VERSION 5.8 ;
BUSBITCHARS "[]" ;
DIVIDERCHAR "/" ;
UNITS
    DATABASE MICRONS 1000 ;
END UNITS

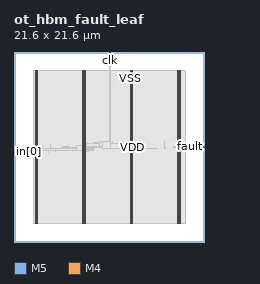
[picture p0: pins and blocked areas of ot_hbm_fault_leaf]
MACRO ot_hbm_fault_leaf
  FOREIGN ot_hbm_fault_leaf 0 0 ;
  CLASS BLOCK ;
  SIZE 21.6 BY 21.6 ;
  PIN clk
    DIRECTION INPUT ;
    USE SIGNAL ;
    PORT
      LAYER M5 ;
        RECT  10.896 21.516 10.92 21.6 ;
    END
  END clk
  PIN fault
    DIRECTION OUTPUT ;
    USE SIGNAL ;
    PORT
      LAYER M4 ;
        RECT  21.516 10.8 21.6 10.824 ;
    END
    PORT
      LAYER M4 ;
        RECT  20.473 10.8 21.564 10.824 ;
    END
  END fault
  PIN in[0]
    DIRECTION INPUT ;
    USE SIGNAL ;
    PORT
      LAYER M4 ;
        RECT  0 10.32 0.084 10.344 ;
    END
  END in[0]
  PIN in[1]
    DIRECTION INPUT ;
    USE SIGNAL ;
    PORT
      LAYER M4 ;
        RECT  0 10.416 0.084 10.44 ;
    END
  END in[1]
  PIN in[2]
    DIRECTION INPUT ;
    USE SIGNAL ;
    PORT
      LAYER M4 ;
        RECT  0 10.512 0.084 10.536 ;
    END
  END in[2]
  PIN in[3]
    DIRECTION INPUT ;
    USE SIGNAL ;
    PORT
      LAYER M4 ;
        RECT  0 10.608 0.084 10.632 ;
    END
  END in[3]
  PIN in[4]
    DIRECTION INPUT ;
    USE SIGNAL ;
    PORT
      LAYER M4 ;
        RECT  0 10.704 0.084 10.728 ;
    END
  END in[4]
  PIN rst_n
    DIRECTION INPUT ;
    USE SIGNAL ;
    PORT
      LAYER M5 ;
        RECT  10.992 21.516 11.016 21.6 ;
    END
  END rst_n
  PIN VDD
    DIRECTION INOUT ;
    USE POWER ;
    PORT
      LAYER M5 ;
        RECT  18.792 2.151 18.912 19.449 ;
        RECT  13.392 2.151 13.512 19.449 ;
        RECT  7.992 2.151 8.112 19.449 ;
        RECT  2.592 2.151 2.712 19.449 ;
    END
  END VDD
  PIN VSS
    DIRECTION INOUT ;
    USE GROUND ;
    PORT
      LAYER M5 ;
        RECT  18.6 2.137 18.72 19.463 ;
        RECT  13.2 2.137 13.32 19.463 ;
        RECT  7.8 2.137 7.92 19.463 ;
        RECT  2.4 2.137 2.52 19.463 ;
    END
  END VSS
  # OT_OBS_CLOSED layer=M5 d_um=1.536 added=0
  OBS
    LAYER RVTN ;
     RECT  2.16 2.16 19.44 2.295 ;
     RECT  2.16 2.565 19.44 2.835 ;
     RECT  2.16 3.105 19.44 3.375 ;
     RECT  2.16 3.645 19.44 3.915 ;
     RECT  2.16 4.185 19.44 4.455 ;
     RECT  2.16 4.725 19.44 4.995 ;
     RECT  2.16 5.265 19.44 5.535 ;
     RECT  2.16 5.805 19.44 6.075 ;
     RECT  2.16 6.345 19.44 6.615 ;
     RECT  2.16 6.885 19.44 7.155 ;
     RECT  2.16 7.425 19.44 7.695 ;
     RECT  2.16 7.965 19.44 8.235 ;
     RECT  2.16 8.505 19.44 8.775 ;
     RECT  2.16 9.045 19.44 9.315 ;
     RECT  2.16 9.585 19.44 9.855 ;
     RECT  2.16 10.125 19.44 10.395 ;
     RECT  2.16 10.665 19.44 10.935 ;
     RECT  2.16 11.205 19.44 11.475 ;
     RECT  2.16 11.745 19.44 12.015 ;
     RECT  2.16 12.285 19.44 12.555 ;
     RECT  2.16 12.825 19.44 13.095 ;
     RECT  2.16 13.365 19.44 13.635 ;
     RECT  2.16 13.905 19.44 14.175 ;
     RECT  2.16 14.445 19.44 14.715 ;
     RECT  2.16 14.985 19.44 15.255 ;
     RECT  2.16 15.525 19.44 15.795 ;
     RECT  2.16 16.065 19.44 16.335 ;
     RECT  2.16 16.605 19.44 16.875 ;
     RECT  2.16 17.145 19.44 17.415 ;
     RECT  2.16 17.685 19.44 17.955 ;
     RECT  2.16 18.225 19.44 18.495 ;
     RECT  2.16 18.765 19.44 19.035 ;
     RECT  2.16 19.305 19.44 19.44 ;
    LAYER RVTP ;
     RECT  2.16 2.295 19.44 2.565 ;
     RECT  2.16 2.835 19.44 3.105 ;
     RECT  2.16 3.375 19.44 3.645 ;
     RECT  2.16 3.915 19.44 4.185 ;
     RECT  2.16 4.455 19.44 4.725 ;
     RECT  2.16 4.995 19.44 5.265 ;
     RECT  2.16 5.535 19.44 5.805 ;
     RECT  2.16 6.075 19.44 6.345 ;
     RECT  2.16 6.615 19.44 6.885 ;
     RECT  2.16 7.155 19.44 7.425 ;
     RECT  2.16 7.695 19.44 7.965 ;
     RECT  2.16 8.235 19.44 8.505 ;
     RECT  2.16 8.775 19.44 9.045 ;
     RECT  2.16 9.315 19.44 9.585 ;
     RECT  2.16 9.855 19.44 10.125 ;
     RECT  2.16 10.395 19.44 10.665 ;
     RECT  2.16 10.935 19.44 11.205 ;
     RECT  2.16 11.475 19.44 11.745 ;
     RECT  2.16 12.015 19.44 12.285 ;
     RECT  2.16 12.555 19.44 12.825 ;
     RECT  2.16 13.095 19.44 13.365 ;
     RECT  2.16 13.635 19.44 13.905 ;
     RECT  2.16 14.175 19.44 14.445 ;
     RECT  2.16 14.715 19.44 14.985 ;
     RECT  2.16 15.255 19.44 15.525 ;
     RECT  2.16 15.795 19.44 16.065 ;
     RECT  2.16 16.335 19.44 16.605 ;
     RECT  2.16 16.875 19.44 17.145 ;
     RECT  2.16 17.415 19.44 17.685 ;
     RECT  2.16 17.955 19.44 18.225 ;
     RECT  2.16 18.495 19.44 18.765 ;
     RECT  2.16 19.035 19.44 19.305 ;
    LAYER M1 ;
     RECT  2.16 2.151 19.44 19.449 ;
    LAYER M2 ;
     RECT  2.16 2.151 19.44 19.449 ;
     RECT  19.44 10.836 20.507 10.854 ;
    LAYER M3 ;
     RECT  2.415 2.143 2.505 2.413 ;
     RECT  7.815 2.143 7.905 2.413 ;
     RECT  13.215 2.143 13.305 2.413 ;
     RECT  18.615 2.143 18.705 2.413 ;
     RECT  7.815 2.413 8.097 10.291 ;
     RECT  2.415 2.413 2.697 10.315 ;
     RECT  2.304 10.315 2.697 10.357 ;
     RECT  4.716 10.291 4.734 10.363 ;
     RECT  7.815 10.291 8.442 10.363 ;
     RECT  3.96 10.165 3.978 10.399 ;
     RECT  4.716 10.363 4.878 10.399 ;
     RECT  5.832 10.363 5.85 10.399 ;
     RECT  7.272 10.363 8.442 10.399 ;
     RECT  3.96 10.399 6.426 10.435 ;
     RECT  7.272 10.399 9.09 10.435 ;
     RECT  3.96 10.435 9.09 10.463 ;
     RECT  4.104 10.463 9.09 10.471 ;
     RECT  4.104 10.471 9.126 10.589 ;
     RECT  12.384 10.597 12.402 10.603 ;
     RECT  13.215 2.413 13.497 10.603 ;
     RECT  4.104 10.589 4.518 10.625 ;
     RECT  17.244 10.597 17.262 10.633 ;
     RECT  16.272 10.597 16.29 10.637 ;
     RECT  5.4 10.589 9.126 10.697 ;
     RECT  7.092 10.697 9.126 10.705 ;
     RECT  10.044 10.603 10.062 10.705 ;
     RECT  17.1 10.633 17.262 10.733 ;
     RECT  18.615 2.413 18.897 10.741 ;
     RECT  5.4 10.697 6.174 10.769 ;
     RECT  14.832 10.669 14.85 10.769 ;
     RECT  2.304 10.357 3.222 10.781 ;
     RECT  7.092 10.705 10.062 10.859 ;
     RECT  12.384 10.603 13.497 10.859 ;
     RECT  18.18 10.741 18.897 10.859 ;
     RECT  20.484 10.795 20.502 10.859 ;
     RECT  5.652 10.769 6.174 10.895 ;
     RECT  9 10.859 10.062 10.925 ;
     RECT  2.415 10.781 3.222 10.931 ;
     RECT  7.092 10.859 8.19 10.931 ;
     RECT  4.104 10.625 4.194 10.967 ;
     RECT  6.156 10.895 6.174 10.967 ;
     RECT  4.104 10.967 4.122 11.129 ;
     RECT  7.815 10.931 8.19 11.129 ;
     RECT  12.384 10.859 12.402 11.165 ;
     RECT  9 10.925 9.774 11.174 ;
     RECT  9.036 11.174 9.774 11.309 ;
     RECT  11.196 11.281 11.214 11.399 ;
     RECT  17.1 10.733 17.118 11.399 ;
     RECT  9.756 11.309 9.774 11.405 ;
     RECT  10.98 11.509 10.998 11.549 ;
     RECT  2.415 10.931 2.697 19.187 ;
     RECT  7.815 11.129 8.097 19.187 ;
     RECT  13.215 10.859 13.497 19.187 ;
     RECT  18.615 10.859 18.897 19.187 ;
     RECT  2.415 19.187 2.505 19.457 ;
     RECT  7.815 19.187 7.905 19.457 ;
     RECT  13.215 19.187 13.305 19.457 ;
     RECT  18.615 19.187 18.705 19.457 ;
    LAYER M4 ;
     RECT  0.084 10.32 2.252 10.344 ;
     RECT  0.06 10.344 2.252 10.416 ;
     RECT  0.084 10.416 2.252 10.44 ;
     RECT  0.06 10.44 2.252 10.512 ;
     RECT  0.084 10.512 2.252 10.536 ;
     RECT  0.06 10.536 2.252 10.608 ;
     RECT  0.084 10.608 2.252 10.632 ;
     RECT  0.06 10.632 2.252 10.704 ;
     RECT  0.084 10.704 2.252 10.728 ;
     RECT  2.252 10.32 2.408 10.776 ;
     RECT  2.408 2.148 2.512 19.452 ;
     RECT  2.512 2.418 2.704 19.182 ;
     RECT  2.704 10.368 7.081 10.68 ;
     RECT  7.081 10.368 7.808 10.92 ;
     RECT  7.808 2.148 7.912 19.452 ;
     RECT  7.912 2.418 8.104 19.182 ;
     RECT  8.104 10.416 8.237 11.16 ;
     RECT  8.237 10.896 9.745 11.16 ;
     RECT  9.745 10.896 10.033 11.4 ;
     RECT  10.033 10.608 10.94 11.4 ;
     RECT  10.94 10.608 11.027 11.544 ;
     RECT  11.027 10.608 13.208 11.16 ;
     RECT  13.208 2.148 13.312 19.452 ;
     RECT  13.312 2.418 13.504 19.182 ;
     RECT  13.504 10.608 16.301 10.632 ;
     RECT  18.608 2.148 18.712 19.452 ;
     RECT  18.712 2.418 18.904 19.182 ;
    LAYER M5 ;
     RECT  2.4 2.137 2.52 2.151 ;
     RECT  7.8 2.137 7.92 2.151 ;
     RECT  13.2 2.137 13.32 2.151 ;
     RECT  18.6 2.137 18.72 2.151 ;
     RECT  2.4 2.151 2.712 10.645 ;
     RECT  2.304 10.645 2.712 10.787 ;
     RECT  10.896 11.365 10.92 11.509 ;
     RECT  2.4 10.787 2.712 19.449 ;
     RECT  7.8 2.151 8.112 19.449 ;
     RECT  13.2 2.151 13.512 19.449 ;
     RECT  18.6 2.151 18.912 19.449 ;
     RECT  2.4 19.449 2.52 19.463 ;
     RECT  7.8 19.449 7.92 19.463 ;
     RECT  13.2 19.449 13.32 19.463 ;
     RECT  18.6 19.449 18.72 19.463 ;
     RECT  10.896 11.509 11.016 21.516 ;
     RECT  10.92 21.516 10.992 21.584 ;
  END
END ot_hbm_fault_leaf
END LIBRARY
